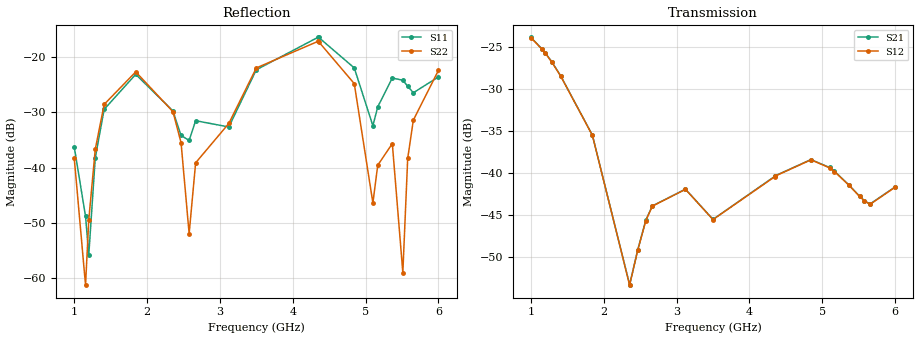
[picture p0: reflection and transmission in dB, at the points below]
!Agilent Technologies,E8364B,MY43040528,A.07.50.67
!Agilent E8364B: A.07.50.67
!Date: Sunday, March 01, 2026 16:27:32
!Correction: S11(Full 2 Port(1,2))
!S21(Full 2 Port(1,2))
!S12(Full 2 Port(1,2))
!S22(Full 2 Port(1,2))
!S2P File: Measurements: S11, S21, S12, S22:
# Hz S  dB  R 50
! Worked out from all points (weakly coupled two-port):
!   451 points, 1 GHz to 6 GHz, reference 50 ohm
!   highest |S21| = -23.82 dB at 1 GHz (marker M1); lowest = -53.2 dB at 2.356 GHz (marker M2)
!   lowest |S11| = -55.8 dB at 1.2 GHz (marker M3), VSWR 1.00, Z = 50.1 - j0.144 ohm
!   |S11| at or under -10 dB: start of sweep to end of sweep
!   |S22| runs from -66.7 to -17.1 dB; largest |S21 - S12| = 0.00028
!   S11 on the Smith chart (normalised r, x): 1 GHz: 1.03, +0.01; 4.356 GHz: 1.20, -0.26; 6 GHz: 0.97, -0.13
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1e9  -36.20 23.4  -23.82 153.3  -23.86 153.3  -38.23 -31.0
1.155556e9  -48.78 7.7  -25.22 64.4  -25.25 64.4  -61.20 -2.9
1.2e9  -55.76 -61.9  -25.69 39.1  -25.72 39.0  -49.42 147.7
1.288889e9  -38.28 -148.7  -26.74 -11.3  -26.78 -11.2  -36.73 143.9
1.411111e9  -29.49 -179.8  -28.43 -79.3  -28.46 -79.2  -28.60 112.8
1.844444e9  -23.18 87.4  -35.45 48.3  -35.48 48.4  -22.73 -0.9
2.355556e9  -29.78 25.8  -53.25 -148.6  -53.30 -148.5  -29.91 -112.8
2.466667e9  -34.19 27.7  -49.11 -163.1  -49.15 -163.0  -35.50 -142.5
2.577778e9  -35.10 67.7  -45.58 149.3  -45.64 149.3  -51.92 110.8
2.666667e9  -31.54 76.6  -43.88 105.1  -43.91 105.1  -39.14 1.8
3.122222e9  -32.67 62.0  -41.88 -135.3  -41.90 -135.3  -32.04 -27.9
3.5e9  -22.35 50.7  -45.48 38.2  -45.50 38.1  -22.02 -104.5
4.344444e9  -16.51 -43.6  -40.37 23.9  -40.42 23.9  -17.24 103.2
4.355556e9  -16.51 -45.3  -40.28 18.0  -40.32 18.0  -17.29 100.7
4.844444e9  -22.02 -125.6  -38.36 102.6  -38.39 102.6  -24.85 -18.8
5.1e9  -32.45 -86.0  -39.30 -48.9  -39.34 -48.9  -46.37 -172.6
5.166667e9  -29.04 -68.4  -39.74 -89.2  -39.78 -89.2  -39.57 97.9
5.366667e9  -23.84 -88.5  -41.39 145.9  -41.42 145.9  -35.67 23.0
5.511111e9  -24.24 -107.7  -42.71 49.5  -42.74 49.5  -58.93 47.7
5.577778e9  -25.33 -112.9  -43.24 2.8  -43.27 2.8  -38.34 120.6
5.655556e9  -26.50 -112.5  -43.65 -53.4  -43.69 -53.3  -31.42 101.8
6e9  -23.64 -100.6  -41.61 61.6  -41.65 61.6  -22.46 3.7
